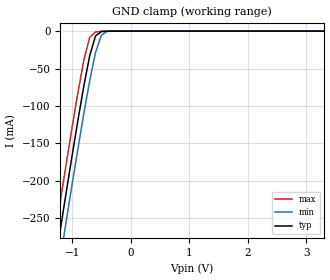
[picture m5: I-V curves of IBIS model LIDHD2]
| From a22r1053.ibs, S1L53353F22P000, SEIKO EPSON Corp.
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[Model]   LIDHD2
Model_type   Input
Polarity   Non-Inverting
Vinh=2.0V
Vinl=0.8V
|   typ   min   max
C_comp   5.0pF   4.0pF   6.0pF
|   typ   min   max
[Voltage range]   3.3   3.0   3.6
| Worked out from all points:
|   GND clamp passes 1 mA (typ) near -0.51 V on its own axis
[GND_clamp]
|   Voltage   I(typ)   I(min)   I(max)
-3.3V     -1.343A    -1.379A    -1.309A
-1.3V     -314.1mA   -352.4mA   -276.2mA
-1.2V     -264.1mA   -302.5mA   -226.1mA
-1.1V     -214.6mA   -253.1mA   -176.6mA
-1V       -165.9mA   -204.3mA   -128.1mA
-900mV    -118.4mA   -156.4mA   -81.34mA
-800mV    -73.09mA   -109.9mA   -38.6mA
-700mV    -32.75mA   -66.19mA   -8.325mA
-600mV    -6.324mA   -28.42mA   -1.135mA
-500mV    -591.9uA   -5.404mA   -244.5uA
-400mV    -60.77uA   -408.4uA   -22.72uA
3.3V      33.01uA    48.7uA     33.01uA
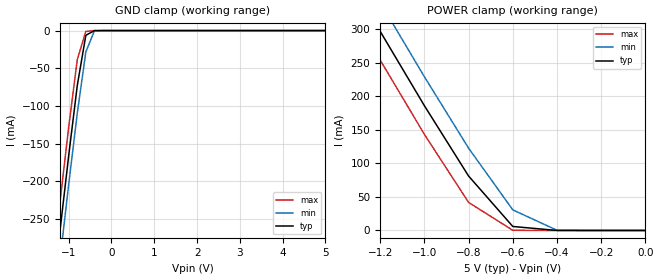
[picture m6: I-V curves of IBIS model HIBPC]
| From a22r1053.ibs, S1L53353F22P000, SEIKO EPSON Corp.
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[Model]   HIBPC
Model_type   Input
Polarity   Non-Inverting
Vinh=2.0V
Vinl=0.8V
|   typ   min   max
C_comp   5.0pF   4.0pF   6.0pF
|   typ   min   max
[Voltage range]   5.0   4.75   5.25
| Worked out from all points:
|   GND clamp passes 1 mA (typ) near -0.43 V on its own axis
|   POWER clamp passes 1 mA (typ) near -0.43 V on its own axis
[GND_clamp]
|   Voltage   I(typ)   I(min)   I(max)
-5V       -2.229A    -2.262A    -2.197A
-1.4V     -364.4mA   -402.6mA   -326.6mA
-1.2V     -264.1mA   -302.5mA   -226.1mA
-1V       -165.9mA   -204.2mA   -128.1mA
-800mV    -73.08mA   -109.9mA   -38.6mA
-600mV    -6.318mA   -28.41mA   -1.129mA
-400mV    -56.78uA   -404.4uA   -18.72uA
5V        10.55nA    3.444uA    9.521nA
[POWER_clamp]
|   Voltage   I(typ)   I(min)   I(max)
-5V       2.513A     2.55A      2.477A
-1.4V     409.9mA    452.7mA    367.4mA
-1.2V     296.7mA    339.9mA    253.9mA
-1V       185.9mA    229mA      143.2mA
-800mV    81.11mA    122.6mA    41.82mA
-600mV    5.968mA    30.7mA     281.7uA
-400mV    15.7uA     326.5uA    2.388uA
0V        10.55nA    21.22nA    10.52nA
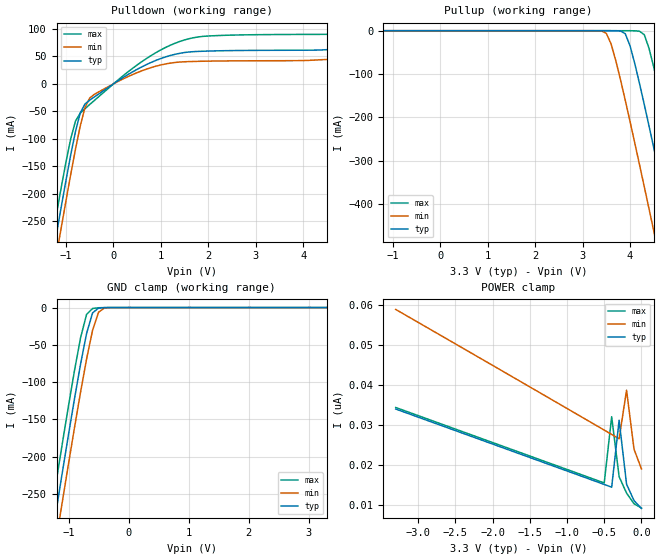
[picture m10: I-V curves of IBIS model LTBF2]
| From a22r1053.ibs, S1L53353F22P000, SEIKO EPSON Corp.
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[Model]   LTBF2
Model_type   Output
Polarity   Non-Inverting
|   typ   min   max
C_comp   5.0pF   4.0pF   6.0pF
|   typ   min   max
[Voltage range]   3.3   3.0   3.6
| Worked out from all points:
|   slope of the pulldown table from 0 to 0.495 V, typ, clamps not added: 18.9 ohm
|   GND clamp passes 1 mA (typ) near -0.51 V on its own axis
[Pulldown]
|   Voltage   I(typ)   I(min)   I(max)
-3.3V     -1.364A    -1.4A      -1.329A
-1.3V     -322.9mA   -361.1mA   -285.9mA
-1.2V     -272.7mA   -310.8mA   -236.2mA
-1.1V     -223.3mA   -261.1mA   -187.9mA
-900mV    -128.8mA   -164.3mA   -99.6mA
-800mV    -86.42mA   -118.6mA   -67.56mA
-700mV    -52.93mA   -76.59mA   -53.26mA
-500mV    -29.6mA    -25.49mA   -37.43mA
400mV     21.67mA    16.83mA    28.06mA
1.2V      51.66mA    37.79mA    70.31mA
2V        59.69mA    41.36mA    87.05mA
6.6V      63.74mA    43.71mA    99.95mA
[Pullup]
|   Voltage   I(typ)   I(min)   I(max)
-3.3V     33.95nA    58.94nA    34.34nA
3.4V      -20.22nA   -470.6uA   -5.615nA
3.6V      -4.286uA   -30.46mA   -6.482nA
3.9V      -7.117mA   -160.6mA   -898.9nA
4V        -34.75mA   -209.2mA   -20.17uA
4.2V      -121.8mA   -308.9mA   -1.232mA
4.3V      -170mA     -359.4mA   -9.189mA
4.5V      -269.6mA   -461.5mA   -84mA
4.9V      -474.2mA   -667.8mA   -281.6mA
5.2V      -629.7mA   -823.8mA   -436mA
5.3V      -681.8mA   -875.9mA   -487.9mA
6.6V      -1.364A    -1.557A    -1.17A
[GND_clamp]
|   Voltage   I(typ)   I(min)   I(max)
-3.3V     -1.364A    -1.4A      -1.329A
-1.3V     -320.3mA   -359.4mA   -281.6mA
-1.2V     -269.6mA   -308.9mA   -230.8mA
-1.1V     -219.5mA   -258.7mA   -180.6mA
-1V       -170.1mA   -209.2mA   -131.4mA
-900mV    -121.9mA   -160.6mA   -84mA
-800mV    -75.86mA   -113.5mA   -40.55mA
-700mV    -34.75mA   -69.08mA   -9.194mA
-600mV    -7.118mA   -30.46mA   -1.232mA
-500mV    -657.9uA   -6.157mA   -258.3uA
-400mV    -61.96uA   -470.6uA   -20.17uA
3.3V      9.002nA    26.5nA     7.679nA
[POWER_clamp]
|   Voltage   I(typ)   I(min)   I(max)
-3.3V     33.95nA    58.94nA    34.34nA
-500mV    15.03nA    28.67nA    15.4nA
-400mV    14.34nA    27.58nA    32.03nA
-300mV    31.14nA    26.48nA    16.98nA
-200mV    15.09nA    38.68nA    12.86nA
-100mV    10.99nA    23.88nA    10.19nA
0V        8.995nA    18.93nA    9.123nA
[Ramp]
|   V_typ   V_min   V_max
dV/dt_r   1.98/1.15n   1.80/1.57n   2.16/0.84n
dV/dt_f   1.98/0.99n   1.80/1.37n   2.16/0.67n
R_load = 5000
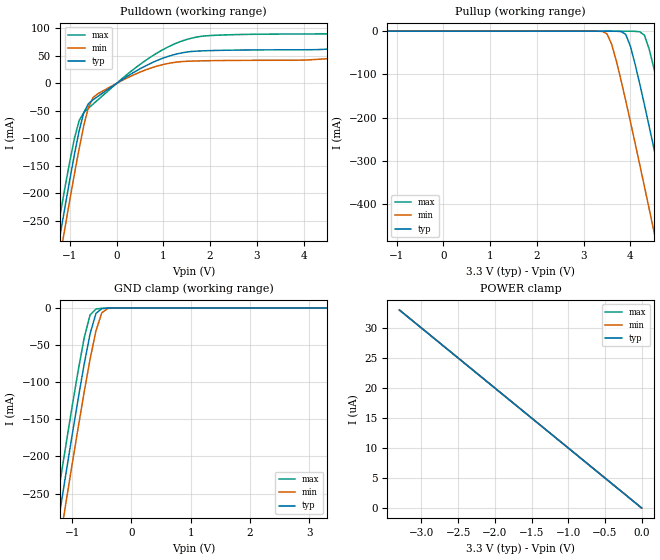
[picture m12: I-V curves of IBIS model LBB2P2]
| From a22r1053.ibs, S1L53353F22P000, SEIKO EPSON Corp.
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[Model]   LBB2P2
Model_type   I/O
Polarity   Non-Inverting
Vinh=2.0V
Vinl=0.8V
|   typ   min   max
C_comp   5.0pF   4.0pF   6.0pF
|   typ   min   max
[Voltage range]   3.3   3.0   3.6
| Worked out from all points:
|   slope of the pulldown table from 0 to 0.495 V, typ, clamps not added: 18.9 ohm
|   slope of the pullup table from 0 to 0.495 V, typ, clamps not added: 99.9 kohm
|   GND clamp passes 1 mA (typ) near -0.50 V on its own axis
[Pulldown]
|   Voltage   I(typ)   I(min)   I(max)
-3.3V     -1.364A    -1.4A      -1.329A
-1.3V     -322.9mA   -361.2mA   -285.9mA
-1.2V     -272.8mA   -310.9mA   -236.3mA
-1.1V     -223.4mA   -261.1mA   -187.9mA
-900mV    -128.9mA   -164.4mA   -99.65mA
-800mV    -86.46mA   -118.6mA   -67.61mA
-700mV    -52.97mA   -76.62mA   -53.3mA
-500mV    -29.64mA   -25.53mA   -37.47mA
400mV     21.64mA    16.8mA     28.03mA
1.2V      51.64mA    37.77mA    70.29mA
2.1V      59.92mA    41.48mA    87.48mA
6.6V      63.75mA    43.75mA    94.12mA
[Pullup]
|   Voltage   I(typ)   I(min)   I(max)
-3.3V     33.03uA    33.06uA    33.03uA
3.4V      -34.02uA   -504.5uA   -34.01uA
3.6V      -40.29uA   -30.49mA   -36.01uA
3.9V      -7.156mA   -160.6mA   -39.9uA
4V        -34.79mA   -209.3mA   -60.17uA
4.2V      -121.8mA   -308.9mA   -1.274mA
4.3V      -170.1mA   -359.5mA   -9.231mA
4.5V      -269.7mA   -461.5mA   -84.04mA
4.9V      -474.2mA   -667.9mA   -281.6mA
5.2V      -629.8mA   -823.8mA   -436.1mA
5.3V      -681.8mA   -876mA     -488mA
6.6V      -1.364A    -1.558A    -1.17A
[GND_clamp]
|   Voltage   I(typ)   I(min)   I(max)
-3.3V     -1.364A    -1.4A      -1.329A
-1.3V     -320.3mA   -359.5mA   -281.6mA
-1.2V     -269.7mA   -308.9mA   -230.9mA
-1.1V     -219.5mA   -258.8mA   -180.7mA
-1V       -170.1mA   -209.3mA   -131.5mA
-900mV    -121.9mA   -160.7mA   -84.05mA
-800mV    -75.9mA    -113.6mA   -40.59mA
-700mV    -34.79mA   -69.11mA   -9.236mA
-600mV    -7.157mA   -30.49mA   -1.274mA
-500mV    -695.8uA   -6.192mA   -299.2uA
-400mV    -98.95uA   -504.6uA   -60.17uA
3.3V      9.077nA    3.026uA    -2.992uA
[POWER_clamp]
|   Voltage   I(typ)   I(min)   I(max)
-3.3V     33.03uA    33.06uA    33.03uA
-300mV    3.014uA    3.026uA    3.018uA
-200mV    2.016uA    2.039uA    2.013uA
0V        9.072nA    19.06nA    9.202nA
[Ramp]
|   V_typ   V_min   V_max
dV/dt_r   1.98/1.10n   1.80/1.54n   2.16/0.75n
dV/dt_f   1.98/0.95n   1.80/1.33n   2.16/0.70n
R_load = 5000
